VERSION 5.8 ;
BUSBITCHARS "[]" ;
DIVIDERCHAR "/" ;
UNITS
    DATABASE MICRONS 1000 ;
END UNITS

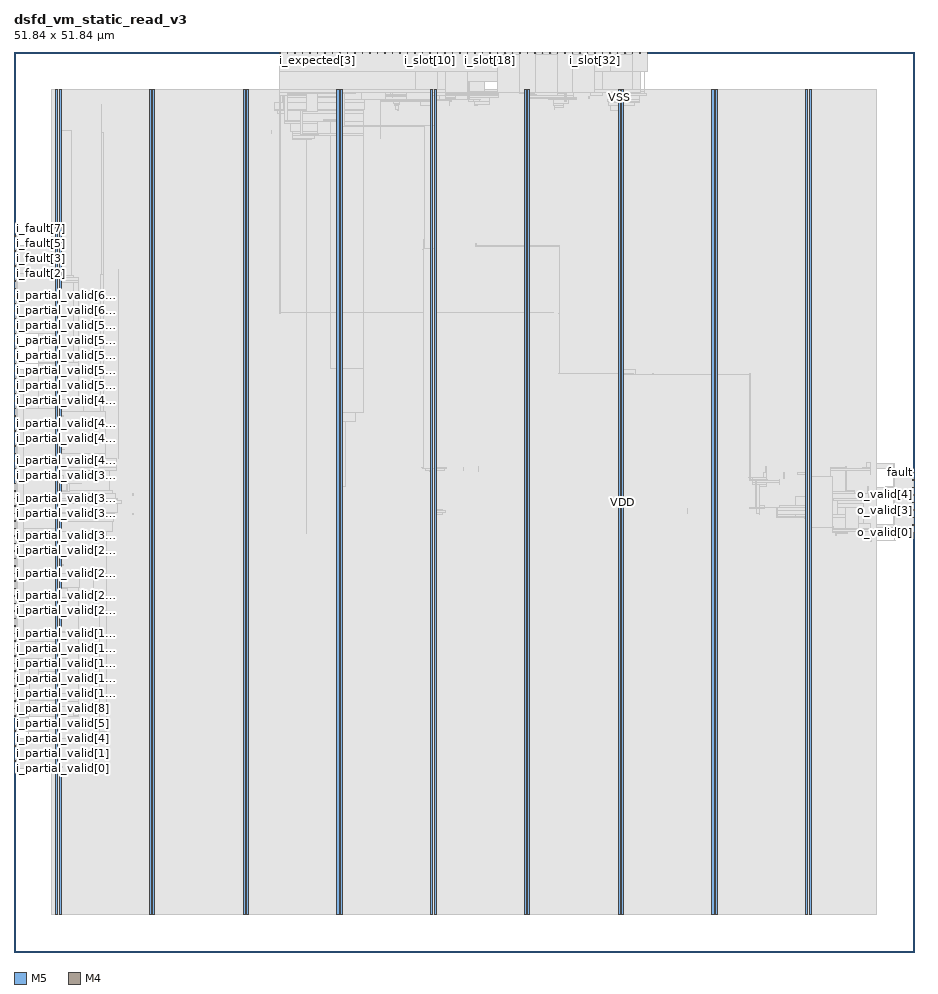
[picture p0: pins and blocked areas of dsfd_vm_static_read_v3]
MACRO dsfd_vm_static_read_v3
  FOREIGN dsfd_vm_static_read_v3 0 0 ;
  CLASS BLOCK ;
  SIZE 51.84 BY 51.84 ;
  PIN ck
    DIRECTION INPUT ;
    USE SIGNAL ;
    PORT
      LAYER M5 ;
        RECT  15.312 51.756 15.336 51.84 ;
    END
  END ck
  PIN fault
    DIRECTION OUTPUT ;
    USE SIGNAL ;
    PORT
      LAYER M4 ;
        RECT  51.756 27.6 51.84 27.624 ;
    END
  END fault
  PIN i_expected[0]
    DIRECTION INPUT ;
    USE SIGNAL ;
    PORT
      LAYER M5 ;
        RECT  16.176 51.756 16.2 51.84 ;
    END
  END i_expected[0]
  PIN i_expected[1]
    DIRECTION INPUT ;
    USE SIGNAL ;
    PORT
      LAYER M5 ;
        RECT  16.608 51.756 16.632 51.84 ;
    END
  END i_expected[1]
  PIN i_expected[2]
    DIRECTION INPUT ;
    USE SIGNAL ;
    PORT
      LAYER M5 ;
        RECT  17.04 51.756 17.064 51.84 ;
    END
  END i_expected[2]
  PIN i_expected[3]
    DIRECTION INPUT ;
    USE SIGNAL ;
    PORT
      LAYER M5 ;
        RECT  17.472 51.756 17.496 51.84 ;
    END
  END i_expected[3]
  PIN i_expected[4]
    DIRECTION INPUT ;
    USE SIGNAL ;
    PORT
      LAYER M5 ;
        RECT  17.904 51.756 17.928 51.84 ;
    END
  END i_expected[4]
  PIN i_expected[5]
    DIRECTION INPUT ;
    USE SIGNAL ;
    PORT
      LAYER M5 ;
        RECT  18.336 51.756 18.36 51.84 ;
    END
  END i_expected[5]
  PIN i_expected[6]
    DIRECTION INPUT ;
    USE SIGNAL ;
    PORT
      LAYER M5 ;
        RECT  18.768 51.756 18.792 51.84 ;
    END
  END i_expected[6]
  PIN i_expected[7]
    DIRECTION INPUT ;
    USE SIGNAL ;
    PORT
      LAYER M5 ;
        RECT  19.2 51.756 19.224 51.84 ;
    END
  END i_expected[7]
  PIN i_fault[0]
    DIRECTION INPUT ;
    USE SIGNAL ;
    PORT
      LAYER M4 ;
        RECT  0 38.208 0.084 38.232 ;
    END
  END i_fault[0]
  PIN i_fault[1]
    DIRECTION INPUT ;
    USE SIGNAL ;
    PORT
      LAYER M4 ;
        RECT  0 38.64 0.084 38.664 ;
    END
  END i_fault[1]
  PIN i_fault[2]
    DIRECTION INPUT ;
    USE SIGNAL ;
    PORT
      LAYER M4 ;
        RECT  0 39.072 0.084 39.096 ;
    END
  END i_fault[2]
  PIN i_fault[3]
    DIRECTION INPUT ;
    USE SIGNAL ;
    PORT
      LAYER M4 ;
        RECT  0 39.504 0.084 39.528 ;
    END
  END i_fault[3]
  PIN i_fault[4]
    DIRECTION INPUT ;
    USE SIGNAL ;
    PORT
      LAYER M4 ;
        RECT  0 39.936 0.084 39.96 ;
    END
  END i_fault[4]
  PIN i_fault[5]
    DIRECTION INPUT ;
    USE SIGNAL ;
    PORT
      LAYER M4 ;
        RECT  0 40.368 0.084 40.392 ;
    END
  END i_fault[5]
  PIN i_fault[6]
    DIRECTION INPUT ;
    USE SIGNAL ;
    PORT
      LAYER M4 ;
        RECT  0 40.8 0.084 40.824 ;
    END
  END i_fault[6]
  PIN i_fault[7]
    DIRECTION INPUT ;
    USE SIGNAL ;
    PORT
      LAYER M4 ;
        RECT  0 41.232 0.084 41.256 ;
    END
  END i_fault[7]
  PIN i_partial_valid[0]
    DIRECTION INPUT ;
    USE SIGNAL ;
    PORT
      LAYER M4 ;
        RECT  0 10.56 0.084 10.584 ;
    END
  END i_partial_valid[0]
  PIN i_partial_valid[10]
    DIRECTION INPUT ;
    USE SIGNAL ;
    PORT
      LAYER M4 ;
        RECT  0 14.88 0.084 14.904 ;
    END
  END i_partial_valid[10]
  PIN i_partial_valid[11]
    DIRECTION INPUT ;
    USE SIGNAL ;
    PORT
      LAYER M4 ;
        RECT  0 15.312 0.084 15.336 ;
    END
  END i_partial_valid[11]
  PIN i_partial_valid[12]
    DIRECTION INPUT ;
    USE SIGNAL ;
    PORT
      LAYER M4 ;
        RECT  0 15.744 0.084 15.768 ;
    END
  END i_partial_valid[12]
  PIN i_partial_valid[13]
    DIRECTION INPUT ;
    USE SIGNAL ;
    PORT
      LAYER M4 ;
        RECT  0 16.176 0.084 16.2 ;
    END
  END i_partial_valid[13]
  PIN i_partial_valid[14]
    DIRECTION INPUT ;
    USE SIGNAL ;
    PORT
      LAYER M4 ;
        RECT  0 16.608 0.084 16.632 ;
    END
  END i_partial_valid[14]
  PIN i_partial_valid[15]
    DIRECTION INPUT ;
    USE SIGNAL ;
    PORT
      LAYER M4 ;
        RECT  0 17.04 0.084 17.064 ;
    END
  END i_partial_valid[15]
  PIN i_partial_valid[16]
    DIRECTION INPUT ;
    USE SIGNAL ;
    PORT
      LAYER M4 ;
        RECT  0 17.472 0.084 17.496 ;
    END
  END i_partial_valid[16]
  PIN i_partial_valid[17]
    DIRECTION INPUT ;
    USE SIGNAL ;
    PORT
      LAYER M4 ;
        RECT  0 17.904 0.084 17.928 ;
    END
  END i_partial_valid[17]
  PIN i_partial_valid[18]
    DIRECTION INPUT ;
    USE SIGNAL ;
    PORT
      LAYER M4 ;
        RECT  0 18.336 0.084 18.36 ;
    END
  END i_partial_valid[18]
  PIN i_partial_valid[19]
    DIRECTION INPUT ;
    USE SIGNAL ;
    PORT
      LAYER M4 ;
        RECT  0 18.768 0.084 18.792 ;
    END
  END i_partial_valid[19]
  PIN i_partial_valid[1]
    DIRECTION INPUT ;
    USE SIGNAL ;
    PORT
      LAYER M4 ;
        RECT  0 10.992 0.084 11.016 ;
    END
  END i_partial_valid[1]
  PIN i_partial_valid[20]
    DIRECTION INPUT ;
    USE SIGNAL ;
    PORT
      LAYER M4 ;
        RECT  0 19.2 0.084 19.224 ;
    END
  END i_partial_valid[20]
  PIN i_partial_valid[21]
    DIRECTION INPUT ;
    USE SIGNAL ;
    PORT
      LAYER M4 ;
        RECT  0 19.632 0.084 19.656 ;
    END
  END i_partial_valid[21]
  PIN i_partial_valid[22]
    DIRECTION INPUT ;
    USE SIGNAL ;
    PORT
      LAYER M4 ;
        RECT  0 20.064 0.084 20.088 ;
    END
  END i_partial_valid[22]
  PIN i_partial_valid[23]
    DIRECTION INPUT ;
    USE SIGNAL ;
    PORT
      LAYER M4 ;
        RECT  0 20.496 0.084 20.52 ;
    END
  END i_partial_valid[23]
  PIN i_partial_valid[24]
    DIRECTION INPUT ;
    USE SIGNAL ;
    PORT
      LAYER M4 ;
        RECT  0 20.928 0.084 20.952 ;
    END
  END i_partial_valid[24]
  PIN i_partial_valid[25]
    DIRECTION INPUT ;
    USE SIGNAL ;
    PORT
      LAYER M4 ;
        RECT  0 21.36 0.084 21.384 ;
    END
  END i_partial_valid[25]
  PIN i_partial_valid[26]
    DIRECTION INPUT ;
    USE SIGNAL ;
    PORT
      LAYER M4 ;
        RECT  0 21.792 0.084 21.816 ;
    END
  END i_partial_valid[26]
  PIN i_partial_valid[27]
    DIRECTION INPUT ;
    USE SIGNAL ;
    PORT
      LAYER M4 ;
        RECT  0 22.224 0.084 22.248 ;
    END
  END i_partial_valid[27]
  PIN i_partial_valid[28]
    DIRECTION INPUT ;
    USE SIGNAL ;
    PORT
      LAYER M4 ;
        RECT  0 22.656 0.084 22.68 ;
    END
  END i_partial_valid[28]
  PIN i_partial_valid[29]
    DIRECTION INPUT ;
    USE SIGNAL ;
    PORT
      LAYER M4 ;
        RECT  0 23.088 0.084 23.112 ;
    END
  END i_partial_valid[29]
  PIN i_partial_valid[2]
    DIRECTION INPUT ;
    USE SIGNAL ;
    PORT
      LAYER M4 ;
        RECT  0 11.424 0.084 11.448 ;
    END
  END i_partial_valid[2]
  PIN i_partial_valid[30]
    DIRECTION INPUT ;
    USE SIGNAL ;
    PORT
      LAYER M4 ;
        RECT  0 23.52 0.084 23.544 ;
    END
  END i_partial_valid[30]
  PIN i_partial_valid[31]
    DIRECTION INPUT ;
    USE SIGNAL ;
    PORT
      LAYER M4 ;
        RECT  0 23.952 0.084 23.976 ;
    END
  END i_partial_valid[31]
  PIN i_partial_valid[32]
    DIRECTION INPUT ;
    USE SIGNAL ;
    PORT
      LAYER M4 ;
        RECT  0 24.384 0.084 24.408 ;
    END
  END i_partial_valid[32]
  PIN i_partial_valid[33]
    DIRECTION INPUT ;
    USE SIGNAL ;
    PORT
      LAYER M4 ;
        RECT  0 24.816 0.084 24.84 ;
    END
  END i_partial_valid[33]
  PIN i_partial_valid[34]
    DIRECTION INPUT ;
    USE SIGNAL ;
    PORT
      LAYER M4 ;
        RECT  0 25.248 0.084 25.272 ;
    END
  END i_partial_valid[34]
  PIN i_partial_valid[35]
    DIRECTION INPUT ;
    USE SIGNAL ;
    PORT
      LAYER M4 ;
        RECT  0 25.68 0.084 25.704 ;
    END
  END i_partial_valid[35]
  PIN i_partial_valid[36]
    DIRECTION INPUT ;
    USE SIGNAL ;
    PORT
      LAYER M4 ;
        RECT  0 26.112 0.084 26.136 ;
    END
  END i_partial_valid[36]
  PIN i_partial_valid[37]
    DIRECTION INPUT ;
    USE SIGNAL ;
    PORT
      LAYER M4 ;
        RECT  0 26.544 0.084 26.568 ;
    END
  END i_partial_valid[37]
  PIN i_partial_valid[38]
    DIRECTION INPUT ;
    USE SIGNAL ;
    PORT
      LAYER M4 ;
        RECT  0 26.976 0.084 27 ;
    END
  END i_partial_valid[38]
  PIN i_partial_valid[39]
    DIRECTION INPUT ;
    USE SIGNAL ;
    PORT
      LAYER M4 ;
        RECT  0 27.408 0.084 27.432 ;
    END
  END i_partial_valid[39]
  PIN i_partial_valid[3]
    DIRECTION INPUT ;
    USE SIGNAL ;
    PORT
      LAYER M4 ;
        RECT  0 11.856 0.084 11.88 ;
    END
  END i_partial_valid[3]
  PIN i_partial_valid[40]
    DIRECTION INPUT ;
    USE SIGNAL ;
    PORT
      LAYER M4 ;
        RECT  0 27.84 0.084 27.864 ;
    END
  END i_partial_valid[40]
  PIN i_partial_valid[41]
    DIRECTION INPUT ;
    USE SIGNAL ;
    PORT
      LAYER M4 ;
        RECT  0 28.272 0.084 28.296 ;
    END
  END i_partial_valid[41]
  PIN i_partial_valid[42]
    DIRECTION INPUT ;
    USE SIGNAL ;
    PORT
      LAYER M4 ;
        RECT  0 28.704 0.084 28.728 ;
    END
  END i_partial_valid[42]
  PIN i_partial_valid[43]
    DIRECTION INPUT ;
    USE SIGNAL ;
    PORT
      LAYER M4 ;
        RECT  0 29.136 0.084 29.16 ;
    END
  END i_partial_valid[43]
  PIN i_partial_valid[44]
    DIRECTION INPUT ;
    USE SIGNAL ;
    PORT
      LAYER M4 ;
        RECT  0 29.568 0.084 29.592 ;
    END
  END i_partial_valid[44]
  PIN i_partial_valid[45]
    DIRECTION INPUT ;
    USE SIGNAL ;
    PORT
      LAYER M4 ;
        RECT  0 30 0.084 30.024 ;
    END
  END i_partial_valid[45]
  PIN i_partial_valid[46]
    DIRECTION INPUT ;
    USE SIGNAL ;
    PORT
      LAYER M4 ;
        RECT  0 30.432 0.084 30.456 ;
    END
  END i_partial_valid[46]
  PIN i_partial_valid[47]
    DIRECTION INPUT ;
    USE SIGNAL ;
    PORT
      LAYER M4 ;
        RECT  0 30.864 0.084 30.888 ;
    END
  END i_partial_valid[47]
  PIN i_partial_valid[48]
    DIRECTION INPUT ;
    USE SIGNAL ;
    PORT
      LAYER M4 ;
        RECT  0 31.296 0.084 31.32 ;
    END
  END i_partial_valid[48]
  PIN i_partial_valid[49]
    DIRECTION INPUT ;
    USE SIGNAL ;
    PORT
      LAYER M4 ;
        RECT  0 31.728 0.084 31.752 ;
    END
  END i_partial_valid[49]
  PIN i_partial_valid[4]
    DIRECTION INPUT ;
    USE SIGNAL ;
    PORT
      LAYER M4 ;
        RECT  0 12.288 0.084 12.312 ;
    END
  END i_partial_valid[4]
  PIN i_partial_valid[50]
    DIRECTION INPUT ;
    USE SIGNAL ;
    PORT
      LAYER M4 ;
        RECT  0 32.16 0.084 32.184 ;
    END
  END i_partial_valid[50]
  PIN i_partial_valid[51]
    DIRECTION INPUT ;
    USE SIGNAL ;
    PORT
      LAYER M4 ;
        RECT  0 32.592 0.084 32.616 ;
    END
  END i_partial_valid[51]
  PIN i_partial_valid[52]
    DIRECTION INPUT ;
    USE SIGNAL ;
    PORT
      LAYER M4 ;
        RECT  0 33.024 0.084 33.048 ;
    END
  END i_partial_valid[52]
  PIN i_partial_valid[53]
    DIRECTION INPUT ;
    USE SIGNAL ;
    PORT
      LAYER M4 ;
        RECT  0 33.456 0.084 33.48 ;
    END
  END i_partial_valid[53]
  PIN i_partial_valid[54]
    DIRECTION INPUT ;
    USE SIGNAL ;
    PORT
      LAYER M4 ;
        RECT  0 33.888 0.084 33.912 ;
    END
  END i_partial_valid[54]
  PIN i_partial_valid[55]
    DIRECTION INPUT ;
    USE SIGNAL ;
    PORT
      LAYER M4 ;
        RECT  0 34.32 0.084 34.344 ;
    END
  END i_partial_valid[55]
  PIN i_partial_valid[56]
    DIRECTION INPUT ;
    USE SIGNAL ;
    PORT
      LAYER M4 ;
        RECT  0 34.752 0.084 34.776 ;
    END
  END i_partial_valid[56]
  PIN i_partial_valid[57]
    DIRECTION INPUT ;
    USE SIGNAL ;
    PORT
      LAYER M4 ;
        RECT  0 35.184 0.084 35.208 ;
    END
  END i_partial_valid[57]
  PIN i_partial_valid[58]
    DIRECTION INPUT ;
    USE SIGNAL ;
    PORT
      LAYER M4 ;
        RECT  0 35.616 0.084 35.64 ;
    END
  END i_partial_valid[58]
  PIN i_partial_valid[59]
    DIRECTION INPUT ;
    USE SIGNAL ;
    PORT
      LAYER M4 ;
        RECT  0 36.048 0.084 36.072 ;
    END
  END i_partial_valid[59]
  PIN i_partial_valid[5]
    DIRECTION INPUT ;
    USE SIGNAL ;
    PORT
      LAYER M4 ;
        RECT  0 12.72 0.084 12.744 ;
    END
  END i_partial_valid[5]
  PIN i_partial_valid[60]
    DIRECTION INPUT ;
    USE SIGNAL ;
    PORT
      LAYER M4 ;
        RECT  0 36.48 0.084 36.504 ;
    END
  END i_partial_valid[60]
  PIN i_partial_valid[61]
    DIRECTION INPUT ;
    USE SIGNAL ;
    PORT
      LAYER M4 ;
        RECT  0 36.912 0.084 36.936 ;
    END
  END i_partial_valid[61]
  PIN i_partial_valid[62]
    DIRECTION INPUT ;
    USE SIGNAL ;
    PORT
      LAYER M4 ;
        RECT  0 37.344 0.084 37.368 ;
    END
  END i_partial_valid[62]
  PIN i_partial_valid[63]
    DIRECTION INPUT ;
    USE SIGNAL ;
    PORT
      LAYER M4 ;
        RECT  0 37.776 0.084 37.8 ;
    END
  END i_partial_valid[63]
  PIN i_partial_valid[6]
    DIRECTION INPUT ;
    USE SIGNAL ;
    PORT
      LAYER M4 ;
        RECT  0 13.152 0.084 13.176 ;
    END
  END i_partial_valid[6]
  PIN i_partial_valid[7]
    DIRECTION INPUT ;
    USE SIGNAL ;
    PORT
      LAYER M4 ;
        RECT  0 13.584 0.084 13.608 ;
    END
  END i_partial_valid[7]
  PIN i_partial_valid[8]
    DIRECTION INPUT ;
    USE SIGNAL ;
    PORT
      LAYER M4 ;
        RECT  0 14.016 0.084 14.04 ;
    END
  END i_partial_valid[8]
  PIN i_partial_valid[9]
    DIRECTION INPUT ;
    USE SIGNAL ;
    PORT
      LAYER M4 ;
        RECT  0 14.448 0.084 14.472 ;
    END
  END i_partial_valid[9]
  PIN i_slot[0]
    DIRECTION INPUT ;
    USE SIGNAL ;
    PORT
      LAYER M5 ;
        RECT  19.632 51.756 19.656 51.84 ;
    END
  END i_slot[0]
  PIN i_slot[10]
    DIRECTION INPUT ;
    USE SIGNAL ;
    PORT
      LAYER M5 ;
        RECT  23.952 51.756 23.976 51.84 ;
    END
  END i_slot[10]
  PIN i_slot[11]
    DIRECTION INPUT ;
    USE SIGNAL ;
    PORT
      LAYER M5 ;
        RECT  24.384 51.756 24.408 51.84 ;
    END
  END i_slot[11]
  PIN i_slot[12]
    DIRECTION INPUT ;
    USE SIGNAL ;
    PORT
      LAYER M5 ;
        RECT  24.816 51.756 24.84 51.84 ;
    END
  END i_slot[12]
  PIN i_slot[13]
    DIRECTION INPUT ;
    USE SIGNAL ;
    PORT
      LAYER M5 ;
        RECT  25.248 51.756 25.272 51.84 ;
    END
  END i_slot[13]
  PIN i_slot[14]
    DIRECTION INPUT ;
    USE SIGNAL ;
    PORT
      LAYER M5 ;
        RECT  25.68 51.756 25.704 51.84 ;
    END
  END i_slot[14]
  PIN i_slot[15]
    DIRECTION INPUT ;
    USE SIGNAL ;
    PORT
      LAYER M5 ;
        RECT  26.112 51.756 26.136 51.84 ;
    END
  END i_slot[15]
  PIN i_slot[16]
    DIRECTION INPUT ;
    USE SIGNAL ;
    PORT
      LAYER M5 ;
        RECT  26.544 51.756 26.568 51.84 ;
    END
  END i_slot[16]
  PIN i_slot[17]
    DIRECTION INPUT ;
    USE SIGNAL ;
    PORT
      LAYER M5 ;
        RECT  26.976 51.756 27 51.84 ;
    END
  END i_slot[17]
  PIN i_slot[18]
    DIRECTION INPUT ;
    USE SIGNAL ;
    PORT
      LAYER M5 ;
        RECT  27.408 51.756 27.432 51.84 ;
    END
  END i_slot[18]
  PIN i_slot[19]
    DIRECTION INPUT ;
    USE SIGNAL ;
    PORT
      LAYER M5 ;
        RECT  27.84 51.756 27.864 51.84 ;
    END
  END i_slot[19]
  PIN i_slot[1]
    DIRECTION INPUT ;
    USE SIGNAL ;
    PORT
      LAYER M5 ;
        RECT  20.064 51.756 20.088 51.84 ;
    END
  END i_slot[1]
  PIN i_slot[20]
    DIRECTION INPUT ;
    USE SIGNAL ;
    PORT
      LAYER M5 ;
        RECT  28.272 51.756 28.296 51.84 ;
    END
  END i_slot[20]
  PIN i_slot[21]
    DIRECTION INPUT ;
    USE SIGNAL ;
    PORT
      LAYER M5 ;
        RECT  28.704 51.756 28.728 51.84 ;
    END
  END i_slot[21]
  PIN i_slot[22]
    DIRECTION INPUT ;
    USE SIGNAL ;
    PORT
      LAYER M5 ;
        RECT  29.136 51.756 29.16 51.84 ;
    END
  END i_slot[22]
  PIN i_slot[23]
    DIRECTION INPUT ;
    USE SIGNAL ;
    PORT
      LAYER M5 ;
        RECT  29.568 51.756 29.592 51.84 ;
    END
  END i_slot[23]
  PIN i_slot[24]
    DIRECTION INPUT ;
    USE SIGNAL ;
    PORT
      LAYER M5 ;
        RECT  30 51.756 30.024 51.84 ;
    END
  END i_slot[24]
  PIN i_slot[25]
    DIRECTION INPUT ;
    USE SIGNAL ;
    PORT
      LAYER M5 ;
        RECT  30.432 51.756 30.456 51.84 ;
    END
  END i_slot[25]
  PIN i_slot[26]
    DIRECTION INPUT ;
    USE SIGNAL ;
    PORT
      LAYER M5 ;
        RECT  30.864 51.756 30.888 51.84 ;
    END
  END i_slot[26]
  PIN i_slot[27]
    DIRECTION INPUT ;
    USE SIGNAL ;
    PORT
      LAYER M5 ;
        RECT  31.296 51.756 31.32 51.84 ;
    END
  END i_slot[27]
  PIN i_slot[28]
    DIRECTION INPUT ;
    USE SIGNAL ;
    PORT
      LAYER M5 ;
        RECT  31.728 51.756 31.752 51.84 ;
    END
  END i_slot[28]
  PIN i_slot[29]
    DIRECTION INPUT ;
    USE SIGNAL ;
    PORT
      LAYER M5 ;
        RECT  32.16 51.756 32.184 51.84 ;
    END
  END i_slot[29]
  PIN i_slot[2]
    DIRECTION INPUT ;
    USE SIGNAL ;
    PORT
      LAYER M5 ;
        RECT  20.496 51.756 20.52 51.84 ;
    END
  END i_slot[2]
  PIN i_slot[30]
    DIRECTION INPUT ;
    USE SIGNAL ;
    PORT
      LAYER M5 ;
        RECT  32.592 51.756 32.616 51.84 ;
    END
  END i_slot[30]
  PIN i_slot[31]
    DIRECTION INPUT ;
    USE SIGNAL ;
    PORT
      LAYER M5 ;
        RECT  33.024 51.756 33.048 51.84 ;
    END
  END i_slot[31]
  PIN i_slot[32]
    DIRECTION INPUT ;
    USE SIGNAL ;
    PORT
      LAYER M5 ;
        RECT  33.456 51.756 33.48 51.84 ;
    END
  END i_slot[32]
  PIN i_slot[33]
    DIRECTION INPUT ;
    USE SIGNAL ;
    PORT
      LAYER M5 ;
        RECT  33.888 51.756 33.912 51.84 ;
    END
  END i_slot[33]
  PIN i_slot[34]
    DIRECTION INPUT ;
    USE SIGNAL ;
    PORT
      LAYER M5 ;
        RECT  34.32 51.756 34.344 51.84 ;
    END
  END i_slot[34]
  PIN i_slot[35]
    DIRECTION INPUT ;
    USE SIGNAL ;
    PORT
      LAYER M5 ;
        RECT  34.752 51.756 34.776 51.84 ;
    END
  END i_slot[35]
  PIN i_slot[36]
    DIRECTION INPUT ;
    USE SIGNAL ;
    PORT
      LAYER M5 ;
        RECT  35.184 51.756 35.208 51.84 ;
    END
  END i_slot[36]
  PIN i_slot[37]
    DIRECTION INPUT ;
    USE SIGNAL ;
    PORT
      LAYER M5 ;
        RECT  35.616 51.756 35.64 51.84 ;
    END
  END i_slot[37]
  PIN i_slot[38]
    DIRECTION INPUT ;
    USE SIGNAL ;
    PORT
      LAYER M5 ;
        RECT  36.048 51.756 36.072 51.84 ;
    END
  END i_slot[38]
  PIN i_slot[39]
    DIRECTION INPUT ;
    USE SIGNAL ;
    PORT
      LAYER M5 ;
        RECT  36.48 51.756 36.504 51.84 ;
    END
  END i_slot[39]
  PIN i_slot[3]
    DIRECTION INPUT ;
    USE SIGNAL ;
    PORT
      LAYER M5 ;
        RECT  20.928 51.756 20.952 51.84 ;
    END
  END i_slot[3]
  PIN i_slot[4]
    DIRECTION INPUT ;
    USE SIGNAL ;
    PORT
      LAYER M5 ;
        RECT  21.36 51.756 21.384 51.84 ;
    END
  END i_slot[4]
  PIN i_slot[5]
    DIRECTION INPUT ;
    USE SIGNAL ;
    PORT
      LAYER M5 ;
        RECT  21.792 51.756 21.816 51.84 ;
    END
  END i_slot[5]
  PIN i_slot[6]
    DIRECTION INPUT ;
    USE SIGNAL ;
    PORT
      LAYER M5 ;
        RECT  22.224 51.756 22.248 51.84 ;
    END
  END i_slot[6]
  PIN i_slot[7]
    DIRECTION INPUT ;
    USE SIGNAL ;
    PORT
      LAYER M5 ;
        RECT  22.656 51.756 22.68 51.84 ;
    END
  END i_slot[7]
  PIN i_slot[8]
    DIRECTION INPUT ;
    USE SIGNAL ;
    PORT
      LAYER M5 ;
        RECT  23.088 51.756 23.112 51.84 ;
    END
  END i_slot[8]
  PIN i_slot[9]
    DIRECTION INPUT ;
    USE SIGNAL ;
    PORT
      LAYER M5 ;
        RECT  23.52 51.756 23.544 51.84 ;
    END
  END i_slot[9]
  PIN o_valid[0]
    DIRECTION OUTPUT ;
    USE SIGNAL ;
    PORT
      LAYER M4 ;
        RECT  51.756 24.144 51.84 24.168 ;
    END
  END o_valid[0]
  PIN o_valid[1]
    DIRECTION OUTPUT ;
    USE SIGNAL ;
    PORT
      LAYER M4 ;
        RECT  51.756 24.576 51.84 24.6 ;
    END
  END o_valid[1]
  PIN o_valid[2]
    DIRECTION OUTPUT ;
    USE SIGNAL ;
    PORT
      LAYER M4 ;
        RECT  51.756 25.008 51.84 25.032 ;
    END
  END o_valid[2]
  PIN o_valid[3]
    DIRECTION OUTPUT ;
    USE SIGNAL ;
    PORT
      LAYER M4 ;
        RECT  51.756 25.44 51.84 25.464 ;
    END
  END o_valid[3]
  PIN o_valid[4]
    DIRECTION OUTPUT ;
    USE SIGNAL ;
    PORT
      LAYER M4 ;
        RECT  51.756 25.872 51.84 25.896 ;
    END
  END o_valid[4]
  PIN o_valid[5]
    DIRECTION OUTPUT ;
    USE SIGNAL ;
    PORT
      LAYER M4 ;
        RECT  51.756 26.304 51.84 26.328 ;
    END
  END o_valid[5]
  PIN o_valid[6]
    DIRECTION OUTPUT ;
    USE SIGNAL ;
    PORT
      LAYER M4 ;
        RECT  51.756 26.736 51.84 26.76 ;
    END
  END o_valid[6]
  PIN o_valid[7]
    DIRECTION OUTPUT ;
    USE SIGNAL ;
    PORT
      LAYER M4 ;
        RECT  51.756 27.168 51.84 27.192 ;
    END
  END o_valid[7]
  PIN rst_n
    DIRECTION INPUT ;
    USE SIGNAL ;
    PORT
      LAYER M5 ;
        RECT  15.744 51.756 15.768 51.84 ;
    END
  END rst_n
  PIN VDD
    DIRECTION INOUT ;
    USE POWER ;
    PORT
      LAYER M5 ;
        RECT  45.792 2.151 45.912 49.689 ;
        RECT  40.392 2.151 40.512 49.689 ;
        RECT  34.992 2.151 35.112 49.689 ;
        RECT  29.592 2.151 29.712 49.689 ;
        RECT  24.192 2.151 24.312 49.689 ;
        RECT  18.792 2.151 18.912 49.689 ;
        RECT  13.392 2.151 13.512 49.689 ;
        RECT  7.992 2.151 8.112 49.689 ;
        RECT  2.592 2.151 2.712 49.689 ;
    END
  END VDD
  PIN VSS
    DIRECTION INOUT ;
    USE GROUND ;
    PORT
      LAYER M5 ;
        RECT  45.6 2.137 45.72 49.703 ;
        RECT  40.2 2.137 40.32 49.703 ;
        RECT  34.8 2.137 34.92 49.703 ;
        RECT  29.4 2.137 29.52 49.703 ;
        RECT  24 2.137 24.12 49.703 ;
        RECT  18.6 2.137 18.72 49.703 ;
        RECT  13.2 2.137 13.32 49.703 ;
        RECT  7.8 2.137 7.92 49.703 ;
        RECT  2.4 2.137 2.52 49.703 ;
    END
  END VSS
  # OT_OBS_CLOSED layer=M5 d_um=1.536 added=22
  OBS
    LAYER RVTN ;
     RECT  2.16 2.16 49.68 2.295 ;
     RECT  2.16 2.565 49.68 2.835 ;
     RECT  2.16 3.105 49.68 3.375 ;
     RECT  2.16 3.645 49.68 3.915 ;
     RECT  2.16 4.185 49.68 4.455 ;
     RECT  2.16 4.725 49.68 4.995 ;
     RECT  2.16 5.265 49.68 5.535 ;
     RECT  2.16 5.805 49.68 6.075 ;
     RECT  2.16 6.345 49.68 6.615 ;
     RECT  2.16 6.885 49.68 7.155 ;
     RECT  2.16 7.425 49.68 7.695 ;
     RECT  2.16 7.965 49.68 8.235 ;
     RECT  2.16 8.505 49.68 8.775 ;
     RECT  2.16 9.045 49.68 9.315 ;
     RECT  2.16 9.585 49.68 9.855 ;
     RECT  2.16 10.125 49.68 10.395 ;
     RECT  2.16 10.665 49.68 10.935 ;
     RECT  2.16 11.205 49.68 11.475 ;
     RECT  2.16 11.745 49.68 12.015 ;
     RECT  2.16 12.285 49.68 12.555 ;
     RECT  2.16 12.825 49.68 13.095 ;
     RECT  2.16 13.365 49.68 13.635 ;
     RECT  2.16 13.905 49.68 14.175 ;
     RECT  2.16 14.445 49.68 14.715 ;
     RECT  2.16 14.985 49.68 15.255 ;
     RECT  2.16 15.525 49.68 15.795 ;
     RECT  2.16 16.065 49.68 16.335 ;
     RECT  2.16 16.605 49.68 16.875 ;
     RECT  2.16 17.145 49.68 17.415 ;
     RECT  2.16 17.685 49.68 17.955 ;
     RECT  2.16 18.225 49.68 18.495 ;
     RECT  2.16 18.765 49.68 19.035 ;
     RECT  2.16 19.305 49.68 19.575 ;
     RECT  2.16 19.845 49.68 20.115 ;
     RECT  2.16 20.385 49.68 20.655 ;
     RECT  2.16 20.925 49.68 21.195 ;
     RECT  2.16 21.465 49.68 21.735 ;
     RECT  2.16 22.005 49.68 22.275 ;
     RECT  2.16 22.545 49.68 22.815 ;
     RECT  2.16 23.085 49.68 23.355 ;
     RECT  2.16 23.625 49.68 23.895 ;
     RECT  2.16 24.165 49.68 24.435 ;
     RECT  2.16 24.705 49.68 24.975 ;
     RECT  2.16 25.245 49.68 25.515 ;
     RECT  2.16 25.785 49.68 26.055 ;
     RECT  2.16 26.325 49.68 26.595 ;
     RECT  2.16 26.865 49.68 27.135 ;
     RECT  2.16 27.405 49.68 27.675 ;
     RECT  2.16 27.945 49.68 28.215 ;
     RECT  2.16 28.485 49.68 28.755 ;
     RECT  2.16 29.025 49.68 29.295 ;
     RECT  2.16 29.565 49.68 29.835 ;
     RECT  2.16 30.105 49.68 30.375 ;
     RECT  2.16 30.645 49.68 30.915 ;
     RECT  2.16 31.185 49.68 31.455 ;
     RECT  2.16 31.725 49.68 31.995 ;
     RECT  2.16 32.265 49.68 32.535 ;
     RECT  2.16 32.805 49.68 33.075 ;
     RECT  2.16 33.345 49.68 33.615 ;
     RECT  2.16 33.885 49.68 34.155 ;
     RECT  2.16 34.425 49.68 34.695 ;
     RECT  2.16 34.965 49.68 35.235 ;
     RECT  2.16 35.505 49.68 35.775 ;
     RECT  2.16 36.045 49.68 36.315 ;
     RECT  2.16 36.585 49.68 36.855 ;
     RECT  2.16 37.125 49.68 37.395 ;
     RECT  2.16 37.665 49.68 37.935 ;
     RECT  2.16 38.205 49.68 38.475 ;
     RECT  2.16 38.745 49.68 39.015 ;
     RECT  2.16 39.285 49.68 39.555 ;
     RECT  2.16 39.825 49.68 40.095 ;
     RECT  2.16 40.365 49.68 40.635 ;
     RECT  2.16 40.905 49.68 41.175 ;
     RECT  2.16 41.445 49.68 41.715 ;
     RECT  2.16 41.985 49.68 42.255 ;
     RECT  2.16 42.525 49.68 42.795 ;
     RECT  2.16 43.065 49.68 43.335 ;
     RECT  2.16 43.605 49.68 43.875 ;
     RECT  2.16 44.145 49.68 44.415 ;
     RECT  2.16 44.685 49.68 44.955 ;
     RECT  2.16 45.225 49.68 45.495 ;
     RECT  2.16 45.765 49.68 46.035 ;
     RECT  2.16 46.305 49.68 46.575 ;
     RECT  2.16 46.845 49.68 47.115 ;
     RECT  2.16 47.385 49.68 47.655 ;
     RECT  2.16 47.925 49.68 48.195 ;
     RECT  2.16 48.465 49.68 48.735 ;
     RECT  2.16 49.005 49.68 49.275 ;
     RECT  2.16 49.545 49.68 49.68 ;
    LAYER RVTP ;
     RECT  2.16 2.295 49.68 2.565 ;
     RECT  2.16 2.835 49.68 3.105 ;
     RECT  2.16 3.375 49.68 3.645 ;
     RECT  2.16 3.915 49.68 4.185 ;
     RECT  2.16 4.455 49.68 4.725 ;
     RECT  2.16 4.995 49.68 5.265 ;
     RECT  2.16 5.535 49.68 5.805 ;
     RECT  2.16 6.075 49.68 6.345 ;
     RECT  2.16 6.615 49.68 6.885 ;
     RECT  2.16 7.155 49.68 7.425 ;
     RECT  2.16 7.695 49.68 7.965 ;
     RECT  2.16 8.235 49.68 8.505 ;
     RECT  2.16 8.775 49.68 9.045 ;
     RECT  2.16 9.315 49.68 9.585 ;
     RECT  2.16 9.855 49.68 10.125 ;
     RECT  2.16 10.395 49.68 10.665 ;
     RECT  2.16 10.935 49.68 11.205 ;
     RECT  2.16 11.475 49.68 11.745 ;
     RECT  2.16 12.015 49.68 12.285 ;
     RECT  2.16 12.555 49.68 12.825 ;
     RECT  2.16 13.095 49.68 13.365 ;
     RECT  2.16 13.635 49.68 13.905 ;
     RECT  2.16 14.175 49.68 14.445 ;
     RECT  2.16 14.715 49.68 14.985 ;
     RECT  2.16 15.255 49.68 15.525 ;
     RECT  2.16 15.795 49.68 16.065 ;
     RECT  2.16 16.335 49.68 16.605 ;
     RECT  2.16 16.875 49.68 17.145 ;
     RECT  2.16 17.415 49.68 17.685 ;
     RECT  2.16 17.955 49.68 18.225 ;
     RECT  2.16 18.495 49.68 18.765 ;
     RECT  2.16 19.035 49.68 19.305 ;
     RECT  2.16 19.575 49.68 19.845 ;
     RECT  2.16 20.115 49.68 20.385 ;
     RECT  2.16 20.655 49.68 20.925 ;
     RECT  2.16 21.195 49.68 21.465 ;
     RECT  2.16 21.735 49.68 22.005 ;
     RECT  2.16 22.275 49.68 22.545 ;
     RECT  2.16 22.815 49.68 23.085 ;
     RECT  2.16 23.355 49.68 23.625 ;
     RECT  2.16 23.895 49.68 24.165 ;
     RECT  2.16 24.435 49.68 24.705 ;
     RECT  2.16 24.975 49.68 25.245 ;
     RECT  2.16 25.515 49.68 25.785 ;
     RECT  2.16 26.055 49.68 26.325 ;
     RECT  2.16 26.595 49.68 26.865 ;
     RECT  2.16 27.135 49.68 27.405 ;
     RECT  2.16 27.675 49.68 27.945 ;
     RECT  2.16 28.215 49.68 28.485 ;
     RECT  2.16 28.755 49.68 29.025 ;
     RECT  2.16 29.295 49.68 29.565 ;
     RECT  2.16 29.835 49.68 30.105 ;
     RECT  2.16 30.375 49.68 30.645 ;
     RECT  2.16 30.915 49.68 31.185 ;
     RECT  2.16 31.455 49.68 31.725 ;
     RECT  2.16 31.995 49.68 32.265 ;
     RECT  2.16 32.535 49.68 32.805 ;
     RECT  2.16 33.075 49.68 33.345 ;
     RECT  2.16 33.615 49.68 33.885 ;
     RECT  2.16 34.155 49.68 34.425 ;
     RECT  2.16 34.695 49.68 34.965 ;
     RECT  2.16 35.235 49.68 35.505 ;
     RECT  2.16 35.775 49.68 36.045 ;
     RECT  2.16 36.315 49.68 36.585 ;
     RECT  2.16 36.855 49.68 37.125 ;
     RECT  2.16 37.395 49.68 37.665 ;
     RECT  2.16 37.935 49.68 38.205 ;
     RECT  2.16 38.475 49.68 38.745 ;
     RECT  2.16 39.015 49.68 39.285 ;
     RECT  2.16 39.555 49.68 39.825 ;
     RECT  2.16 40.095 49.68 40.365 ;
     RECT  2.16 40.635 49.68 40.905 ;
     RECT  2.16 41.175 49.68 41.445 ;
     RECT  2.16 41.715 49.68 41.985 ;
     RECT  2.16 42.255 49.68 42.525 ;
     RECT  2.16 42.795 49.68 43.065 ;
     RECT  2.16 43.335 49.68 43.605 ;
     RECT  2.16 43.875 49.68 44.145 ;
     RECT  2.16 44.415 49.68 44.685 ;
     RECT  2.16 44.955 49.68 45.225 ;
     RECT  2.16 45.495 49.68 45.765 ;
     RECT  2.16 46.035 49.68 46.305 ;
     RECT  2.16 46.575 49.68 46.845 ;
     RECT  2.16 47.115 49.68 47.385 ;
     RECT  2.16 47.655 49.68 47.925 ;
     RECT  2.16 48.195 49.68 48.465 ;
     RECT  2.16 48.735 49.68 49.005 ;
     RECT  2.16 49.275 49.68 49.545 ;
    LAYER M1 ;
     RECT  2.16 2.151 49.68 49.689 ;
    LAYER M2 ;
     RECT  0.067 24.336 0.103 24.354 ;
     RECT  0.103 24.336 0.139 24.768 ;
     RECT  0.067 25.56 0.139 25.578 ;
     RECT  0.103 32.04 0.139 32.058 ;
     RECT  0.103 32.85 0.139 33.57 ;
     RECT  0.103 39.06 0.139 40.158 ;
     RECT  0.103 31.122 0.175 31.14 ;
     RECT  0.175 22.05 0.247 22.23 ;
     RECT  0.175 30.726 0.311 31.14 ;
     RECT  0.175 23.13 0.535 23.148 ;
     RECT  0.139 24.336 0.535 25.578 ;
     RECT  0.103 28.962 0.535 29.358 ;
     RECT  0.311 31.122 0.535 31.14 ;
     RECT  0.139 32.04 0.535 33.57 ;
     RECT  0.535 28.458 0.823 29.358 ;
     RECT  0.535 23.13 1.399 25.578 ;
     RECT  0.823 28.422 1.399 29.358 ;
     RECT  0.247 22.014 1.471 22.23 ;
     RECT  1.399 23.13 1.471 26.01 ;
     RECT  1.471 20.862 1.507 20.88 ;
     RECT  1.399 28.26 1.975 29.358 ;
     RECT  1.471 22.014 2.011 26.01 ;
     RECT  0.103 12.726 2.16 12.744 ;
     RECT  1.507 20.322 2.16 20.88 ;
     RECT  2.011 22.014 2.16 26.118 ;
     RECT  0.031 26.946 2.16 26.964 ;
     RECT  1.975 27.918 2.16 29.358 ;
     RECT  0.535 31.122 2.16 33.57 ;
     RECT  0.139 39.06 2.16 40.698 ;
     RECT  2.16 2.151 49.68 49.689 ;
     RECT  49.68 26.226 50.207 26.784 ;
     RECT  49.68 27.846 50.675 28.134 ;
     RECT  49.68 24.48 50.711 24.624 ;
     RECT  49.68 25.452 50.711 25.47 ;
     RECT  50.207 26.226 50.711 26.514 ;
     RECT  50.675 28.116 50.711 28.134 ;
     RECT  49.68 23.706 50.747 23.724 ;
     RECT  50.711 24.48 50.747 24.498 ;
    LAYER M3 ;
     RECT  2.415 2.143 2.505 2.413 ;
     RECT  7.815 2.143 7.905 2.413 ;
     RECT  13.215 2.143 13.305 2.413 ;
     RECT  18.615 2.143 18.705 2.413 ;
     RECT  24.015 2.143 24.105 2.413 ;
     RECT  29.415 2.143 29.505 2.413 ;
     RECT  34.815 2.143 34.905 2.413 ;
     RECT  40.215 2.143 40.305 2.413 ;
     RECT  45.615 2.143 45.705 2.413 ;
     RECT  2.415 2.413 2.697 10.555 ;
     RECT  2.304 10.555 2.697 10.651 ;
     RECT  2.304 10.651 2.754 10.685 ;
     RECT  0.144 10.987 0.162 11.083 ;
     RECT  0.072 11.083 0.162 11.117 ;
     RECT  2.415 10.685 2.754 11.419 ;
     RECT  0.072 11.117 0.09 12.712 ;
     RECT  0.828 11.851 0.846 12.712 ;
     RECT  5.328 12.283 5.346 12.721 ;
     RECT  0.072 12.712 0.846 13.483 ;
     RECT  1.98 11.419 2.754 14.107 ;
     RECT  3.708 13.579 3.726 14.107 ;
     RECT  0.036 13.483 0.846 14.141 ;
     RECT  0.828 14.141 0.846 14.443 ;
     RECT  1.98 14.107 3.726 14.443 ;
     RECT  0.036 14.141 0.09 14.875 ;
     RECT  0.828 14.443 3.726 14.875 ;
     RECT  4.896 12.721 5.346 19.651 ;
     RECT  0.036 14.875 3.726 21.001 ;
     RECT  0.036 21.001 3.798 21.811 ;
     RECT  4.572 19.651 5.346 21.811 ;
     RECT  49.356 23.665 49.374 24.061 ;
     RECT  47.34 23.971 47.358 24.097 ;
     RECT  47.34 24.097 48.006 24.169 ;
     RECT  0.036 21.811 5.346 24.241 ;
     RECT  47.16 24.169 48.006 24.241 ;
     RECT  49.32 24.061 49.374 24.241 ;
     RECT  47.16 24.241 49.374 24.359 ;
     RECT  47.16 24.359 49.338 24.395 ;
     RECT  50.724 23.701 50.742 24.571 ;
     RECT  50.688 24.571 50.742 24.629 ;
     RECT  48.636 24.395 49.338 24.701 ;
     RECT  0.036 24.241 5.67 24.781 ;
     RECT  45.615 2.413 45.897 24.979 ;
     RECT  45.504 24.979 45.897 25.015 ;
     RECT  50.724 24.629 50.742 25.037 ;
     RECT  47.16 24.395 47.898 25.051 ;
     RECT  24.015 2.413 24.297 25.177 ;
     RECT  45 25.015 45.897 25.177 ;
     RECT  47.124 25.051 47.898 25.205 ;
     RECT  43.956 25.051 43.974 25.213 ;
     RECT  44.748 25.177 45.897 25.213 ;
     RECT  42.912 25.213 42.93 25.249 ;
     RECT  6.84 25.177 6.858 25.277 ;
     RECT  0.036 24.781 5.706 25.285 ;
     RECT  0.036 25.285 5.814 25.321 ;
     RECT  24.015 25.177 24.678 25.321 ;
     RECT  43.956 25.213 45.897 25.411 ;
     RECT  24.015 25.321 24.858 25.439 ;
     RECT  24.015 25.439 24.678 25.475 ;
     RECT  38.772 25.249 38.79 25.547 ;
     RECT  42.768 25.249 42.93 25.555 ;
     RECT  47.448 25.205 47.898 25.591 ;
     RECT  48.636 24.701 48.906 25.591 ;
     RECT  42.372 25.555 43.218 25.613 ;
     RECT  43.956 25.411 46.314 25.613 ;
     RECT  42.912 25.613 43.218 25.709 ;
     RECT  44.1 25.613 46.314 25.709 ;
     RECT  44.1 25.709 44.118 25.745 ;
     RECT  0.036 25.321 5.958 25.825 ;
     RECT  0.036 25.825 6.03 25.861 ;
     RECT  47.448 25.591 48.906 25.861 ;
     RECT  47.448 25.861 48.942 26.011 ;
     RECT  0.036 25.861 6.174 26.015 ;
     RECT  18.615 2.413 18.897 26.095 ;
     RECT  0.036 26.015 5.958 26.123 ;
     RECT  47.16 26.011 48.942 26.131 ;
     RECT  45 25.709 46.314 26.249 ;
     RECT  45.576 26.249 46.314 26.257 ;
     RECT  45.576 26.257 46.386 26.285 ;
     RECT  2.304 26.123 5.85 26.393 ;
     RECT  47.16 26.131 49.194 26.393 ;
     RECT  45.615 26.285 46.386 26.401 ;
     RECT  47.16 26.393 48.402 26.401 ;
     RECT  6.84 26.293 6.858 26.429 ;
     RECT  49.176 26.393 49.194 26.491 ;
     RECT  45.615 26.401 48.402 26.519 ;
     RECT  50.688 25.435 50.706 26.519 ;
     RECT  45.615 26.519 46.854 26.555 ;
     RECT  2.304 26.393 5.67 26.591 ;
     RECT  47.88 26.519 48.402 26.591 ;
     RECT  49.176 26.491 49.338 26.591 ;
     RECT  47.88 26.591 47.934 26.699 ;
     RECT  50.184 26.731 50.67 26.789 ;
     RECT  42.912 25.709 42.93 26.797 ;
     RECT  49.176 26.591 49.194 26.825 ;
     RECT  18.576 26.095 18.897 26.833 ;
     RECT  42.912 26.797 43.326 26.941 ;
     RECT  0.036 26.123 1.494 26.969 ;
     RECT  0.072 26.969 1.494 27.005 ;
     RECT  42.516 26.941 43.326 27.031 ;
     RECT  44.1 26.905 44.118 27.031 ;
     RECT  45.615 26.555 46.386 27.059 ;
     RECT  42.516 27.031 44.118 27.167 ;
     RECT  42.516 27.167 43.362 27.203 ;
     RECT  44.1 27.167 44.118 27.203 ;
     RECT  42.516 27.203 43.326 27.307 ;
     RECT  42.372 27.307 43.326 27.329 ;
     RECT  42.372 27.329 42.39 27.365 ;
     RECT  45.615 27.059 45.897 27.481 ;
     RECT  50.652 26.789 50.67 27.595 ;
     RECT  45.108 27.481 45.897 27.599 ;
     RECT  43.164 27.329 43.326 27.635 ;
     RECT  44.352 27.301 44.37 27.635 ;
     RECT  24.015 25.475 24.297 27.679 ;
     RECT  23.904 27.679 24.297 27.715 ;
     RECT  47.016 27.355 47.034 27.715 ;
     RECT  2.304 26.591 5.49 27.751 ;
     RECT  23.688 27.715 24.297 27.751 ;
     RECT  47.016 27.715 47.178 27.751 ;
     RECT  47.916 26.699 47.934 27.751 ;
     RECT  49.32 27.481 49.338 27.751 ;
     RECT  47.016 27.751 49.338 27.869 ;
     RECT  50.652 27.595 50.706 27.869 ;
     RECT  23.688 27.751 24.822 27.877 ;
     RECT  25.884 27.751 25.902 27.905 ;
     RECT  47.016 27.869 47.934 27.905 ;
     RECT  48.888 27.869 49.338 27.905 ;
     RECT  0.072 27.005 1.458 27.913 ;
     RECT  2.304 27.751 5.922 27.913 ;
     RECT  23.508 27.877 24.894 27.917 ;
     RECT  26.748 27.679 26.766 27.941 ;
     RECT  43.308 27.635 43.326 27.941 ;
     RECT  47.916 27.905 47.934 27.941 ;
     RECT  50.688 27.869 50.706 28.139 ;
     RECT  49.104 27.905 49.338 28.211 ;
     RECT  0.072 27.913 5.922 28.409 ;
     RECT  0.072 28.409 5.274 28.715 ;
     RECT  0.072 28.715 0.558 28.733 ;
     RECT  18.576 26.833 19.098 30.541 ;
     RECT  0.072 28.733 0.306 30.749 ;
     RECT  18.576 30.541 19.674 31.081 ;
     RECT  1.404 28.715 5.274 31.109 ;
     RECT  0.072 30.749 0.198 31.729 ;
     RECT  1.404 31.109 3.978 31.829 ;
     RECT  0.072 31.729 0.558 32.189 ;
     RECT  34.815 2.413 35.097 33.241 ;
     RECT  34.815 33.241 35.694 33.259 ;
     RECT  36.792 33.259 36.81 33.305 ;
     RECT  34.815 33.259 35.802 33.539 ;
     RECT  18.576 31.081 20.106 33.619 ;
     RECT  1.404 31.829 3.69 33.953 ;
     RECT  0.072 32.189 0.198 34.781 ;
     RECT  0.072 34.781 0.162 35.117 ;
     RECT  0.144 35.117 0.162 35.213 ;
     RECT  31.392 36.751 31.41 36.797 ;
     RECT  31.068 36.811 31.086 36.851 ;
     RECT  1.404 33.953 2.697 36.941 ;
     RECT  2.052 36.941 2.697 37.805 ;
     RECT  2.304 37.805 2.697 38.551 ;
     RECT  3.42 33.953 3.69 38.551 ;
     RECT  2.304 38.551 3.69 38.705 ;
     RECT  2.415 38.705 3.69 38.849 ;
     RECT  2.415 38.849 3.438 38.939 ;
     RECT  5.004 31.109 5.166 39.011 ;
     RECT  6.012 28.453 6.03 39.317 ;
     RECT  0.108 39.055 0.126 39.865 ;
     RECT  0.108 39.865 0.162 40.829 ;
     RECT  26.604 40.651 26.622 40.829 ;
     RECT  0.144 40.829 0.162 41.261 ;
     RECT  23.616 27.917 24.297 46.769 ;
     RECT  16.848 24.133 16.866 46.777 ;
     RECT  16.02 46.777 16.038 46.813 ;
     RECT  16.848 46.777 16.938 46.813 ;
     RECT  16.02 46.813 17.154 46.849 ;
     RECT  16.02 46.849 17.334 47.011 ;
     RECT  18.252 33.619 20.106 47.011 ;
     RECT  16.02 47.011 20.106 47.117 ;
     RECT  5.04 39.011 5.166 47.219 ;
     RECT  16.02 47.117 17.478 47.281 ;
     RECT  2.415 38.939 3.33 47.309 ;
     RECT  14.832 47.119 14.85 47.309 ;
     RECT  15.912 47.281 17.478 47.695 ;
     RECT  15.588 47.695 17.478 47.857 ;
     RECT  18.252 47.117 20.106 47.857 ;
     RECT  15.588 47.857 20.106 48.271 ;
     RECT  34.815 33.539 35.097 48.469 ;
     RECT  15.156 48.271 20.106 48.475 ;
     RECT  15.012 48.475 20.106 48.505 ;
     RECT  22.068 48.469 22.158 48.541 ;
     RECT  31.14 48.541 31.158 48.667 ;
     RECT  21.996 48.541 22.158 48.739 ;
     RECT  24.015 46.769 24.297 48.739 ;
     RECT  31.14 48.667 31.662 48.739 ;
     RECT  23.616 48.739 24.297 48.775 ;
     RECT  34.344 48.469 35.097 48.775 ;
     RECT  21.888 48.739 22.158 48.811 ;
     RECT  26.532 48.775 26.694 48.811 ;
     RECT  5.04 47.219 5.058 48.839 ;
     RECT  21.888 48.811 22.23 48.901 ;
     RECT  31.068 48.739 31.662 48.901 ;
     RECT  15.012 48.505 20.178 48.929 ;
     RECT  34.236 48.775 35.766 48.937 ;
     RECT  21.852 48.901 22.23 48.973 ;
     RECT  23.436 48.775 24.297 48.973 ;
     RECT  25.056 48.775 25.074 48.973 ;
     RECT  26.532 48.811 27.378 48.973 ;
     RECT  34.236 48.937 36.018 48.973 ;
     RECT  21.096 46.885 21.114 49.009 ;
     RECT  21.852 48.973 24.297 49.009 ;
     RECT  21.096 49.009 24.297 49.045 ;
     RECT  25.056 48.973 25.182 49.045 ;
     RECT  21.096 49.045 25.182 49.081 ;
     RECT  31.068 48.901 31.914 49.081 ;
     RECT  34.164 48.973 36.018 49.109 ;
     RECT  21.096 49.081 25.254 49.171 ;
     RECT  29.415 2.413 29.697 49.171 ;
     RECT  30.78 49.081 32.382 49.171 ;
     RECT  29.415 49.171 32.382 49.199 ;
     RECT  21.096 49.171 25.434 49.207 ;
     RECT  15.48 48.929 20.178 49.243 ;
     RECT  26.172 48.973 27.378 49.243 ;
     RECT  33.12 49.171 33.138 49.271 ;
     RECT  29.415 49.199 32.202 49.307 ;
     RECT  15.48 49.243 20.286 49.351 ;
     RECT  21.06 49.207 25.434 49.351 ;
     RECT  26.172 49.243 27.918 49.351 ;
     RECT  34.815 49.109 36.018 49.351 ;
     RECT  15.48 49.351 27.918 49.379 ;
     RECT  29.415 49.307 30.114 49.379 ;
     RECT  2.415 47.309 2.697 49.427 ;
     RECT  7.815 2.413 8.097 49.427 ;
     RECT  13.215 2.413 13.497 49.427 ;
     RECT  40.215 2.413 40.497 49.427 ;
     RECT  45.615 27.599 45.897 49.427 ;
     RECT  22.644 49.379 27.918 49.469 ;
     RECT  29.415 49.379 30.006 49.469 ;
     RECT  34.815 49.351 36.45 49.469 ;
     RECT  29.415 49.469 29.862 49.477 ;
     RECT  15.48 49.379 21.69 49.505 ;
     RECT  31.32 49.307 32.202 49.505 ;
     RECT  16.164 49.505 21.69 49.517 ;
     RECT  22.644 49.469 27.81 49.517 ;
     RECT  29.304 49.477 29.862 49.517 ;
     RECT  31.32 49.505 32.022 49.517 ;
     RECT  20.052 49.517 21.69 49.565 ;
     RECT  22.644 49.517 24.105 49.565 ;
     RECT  25.02 49.517 27.81 49.565 ;
     RECT  29.415 49.517 29.862 49.565 ;
     RECT  32.004 49.517 32.022 49.565 ;
     RECT  16.164 49.517 16.614 49.577 ;
     RECT  17.46 49.517 19.026 49.577 ;
     RECT  20.052 49.565 20.07 49.577 ;
     RECT  21.132 49.565 21.69 49.577 ;
     RECT  25.02 49.565 27.09 49.577 ;
     RECT  33.228 49.315 33.894 49.577 ;
     RECT  34.815 49.469 36.342 49.577 ;
     RECT  22.896 49.565 24.105 49.613 ;
     RECT  2.415 49.427 2.505 49.697 ;
     RECT  7.815 49.427 7.905 49.697 ;
     RECT  13.215 49.427 13.305 49.697 ;
     RECT  18.615 49.577 18.81 49.697 ;
     RECT  23.256 49.613 24.105 49.697 ;
     RECT  29.415 49.565 29.574 49.697 ;
     RECT  34.815 49.577 34.905 49.697 ;
     RECT  40.215 49.427 40.305 49.697 ;
     RECT  45.615 49.427 45.705 49.697 ;
     RECT  18.792 49.697 18.81 49.805 ;
     RECT  29.556 49.697 29.574 49.805 ;
     RECT  26.172 49.577 27.09 50.189 ;
     RECT  21.672 49.577 21.69 50.765 ;
     RECT  23.256 49.697 23.886 50.765 ;
     RECT  25.02 49.577 25.362 50.765 ;
     RECT  33.876 49.577 33.894 50.765 ;
     RECT  36.324 49.577 36.342 50.765 ;
     RECT  26.604 50.189 26.622 51.725 ;
    LAYER M4 ;
     RECT  0.025 13.488 0.06 13.512 ;
     RECT  0.06 10.56 0.137 41.256 ;
     RECT  0.137 13.584 0.173 39.096 ;
     RECT  0.137 40.368 0.173 41.256 ;
     RECT  0.173 13.584 0.209 32.184 ;
     RECT  0.173 33.888 0.209 39.096 ;
     RECT  0.209 17.904 0.569 32.184 ;
     RECT  0.209 13.584 0.893 16.92 ;
     RECT  0.893 15.744 1.433 16.92 ;
     RECT  0.137 10.56 2.408 12.312 ;
     RECT  0.893 13.584 2.408 14.472 ;
     RECT  1.433 16.176 2.408 16.92 ;
     RECT  0.569 17.904 2.408 23.112 ;
     RECT  0.569 24.384 2.408 31.32 ;
     RECT  0.209 33.888 2.408 33.912 ;
     RECT  0.209 35.616 2.408 39.096 ;
     RECT  2.408 2.148 2.512 49.692 ;
     RECT  2.512 2.418 2.704 49.422 ;
     RECT  2.704 10.656 2.765 10.68 ;
     RECT  2.704 33.888 2.765 33.912 ;
     RECT  2.704 22.272 2.873 22.296 ;
     RECT  2.704 26.544 2.873 27.432 ;
     RECT  2.704 30.864 2.873 30.888 ;
     RECT  2.704 28.944 2.909 28.968 ;
     RECT  2.704 16.896 3.053 16.92 ;
     RECT  2.704 20.4 3.089 20.952 ;
     RECT  2.873 26.544 3.097 27.048 ;
     RECT  3.097 26.544 3.197 27 ;
     RECT  2.704 18.432 3.233 18.456 ;
     RECT  3.089 20.4 3.341 20.424 ;
     RECT  2.704 13.584 3.413 14.136 ;
     RECT  3.413 13.584 3.737 13.608 ;
     RECT  3.197 26.976 3.881 27 ;
     RECT  2.704 12.288 5.357 12.312 ;
     RECT  5.857 26.064 5.969 26.088 ;
     RECT  7.808 2.148 7.912 49.692 ;
     RECT  7.912 2.418 8.104 49.422 ;
     RECT  13.208 2.148 13.312 49.692 ;
     RECT  13.312 2.418 13.504 49.422 ;
     RECT  15.001 48.48 15.505 48.504 ;
     RECT  15.505 48.48 15.577 49.368 ;
     RECT  15.577 47.904 15.779 49.368 ;
     RECT  15.779 47.904 16.477 48.456 ;
     RECT  16.477 47.088 16.589 48.456 ;
     RECT  16.589 48.432 16.837 48.456 ;
     RECT  16.124 49.536 16.837 49.56 ;
     RECT  16.837 48.432 17.453 49.56 ;
     RECT  16.589 47.088 17.561 47.112 ;
     RECT  15.301 36.816 18.608 36.84 ;
     RECT  17.845 47.904 18.608 47.928 ;
     RECT  17.453 49.296 18.608 49.56 ;
     RECT  18.608 2.148 18.712 49.692 ;
     RECT  18.712 2.418 18.737 49.692 ;
     RECT  18.737 2.418 18.821 49.8 ;
     RECT  18.821 2.418 18.904 49.512 ;
     RECT  18.904 48.768 19.043 49.512 ;
     RECT  19.043 49.104 20.012 49.512 ;
     RECT  20.012 49.104 21.395 49.56 ;
     RECT  21.661 50.736 22.259 50.76 ;
     RECT  21.395 49.104 22.604 49.272 ;
     RECT  23.557 40.464 23.597 40.488 ;
     RECT  23.245 50.736 23.987 50.76 ;
     RECT  23.497 27.888 24.008 27.912 ;
     RECT  18.904 36.816 24.008 36.84 ;
     RECT  23.597 40.464 24.008 41.016 ;
     RECT  18.904 47.568 24.008 47.592 ;
     RECT  22.604 49.104 24.008 49.56 ;
     RECT  24.008 2.148 24.112 49.692 ;
     RECT  24.112 2.418 24.304 49.512 ;
     RECT  24.304 49.104 24.509 49.512 ;
     RECT  24.509 49.104 24.851 49.368 ;
     RECT  24.304 27.888 24.905 27.912 ;
     RECT  25.009 50.736 25.715 50.76 ;
     RECT  24.851 49.104 26.101 49.128 ;
     RECT  26.101 49.104 26.161 49.56 ;
     RECT  26.161 49.104 26.237 50.184 ;
     RECT  26.237 49.104 26.485 49.128 ;
     RECT  26.485 49.008 26.813 49.128 ;
     RECT  26.813 49.104 26.885 49.128 ;
     RECT  26.593 51.696 27.011 51.72 ;
     RECT  26.237 50.16 27.443 50.184 ;
     RECT  27.781 49.536 27.875 49.56 ;
     RECT  24.304 36.816 29.408 36.84 ;
     RECT  26.593 40.656 29.408 40.68 ;
     RECT  29.125 49.488 29.408 49.512 ;
     RECT  29.408 2.148 29.512 49.692 ;
     RECT  29.512 2.418 29.516 49.692 ;
     RECT  29.516 2.418 29.603 49.8 ;
     RECT  29.603 2.418 29.704 49.56 ;
     RECT  29.704 49.536 30.035 49.56 ;
     RECT  29.704 36.816 31.097 36.84 ;
     RECT  31.34 36.768 31.427 36.792 ;
     RECT  29.704 40.656 31.427 40.68 ;
     RECT  31.285 49.488 31.717 49.512 ;
     RECT  31.717 49.008 31.817 49.512 ;
     RECT  31.993 49.536 32.195 49.56 ;
     RECT  33.865 50.736 34.355 50.76 ;
     RECT  31.381 33.312 34.808 33.336 ;
     RECT  33.217 49.536 34.808 49.56 ;
     RECT  34.808 2.148 34.912 49.692 ;
     RECT  34.912 2.418 35.104 49.56 ;
     RECT  35.104 33.264 35.705 33.336 ;
     RECT  35.104 49.536 36.083 49.56 ;
     RECT  36.313 50.736 36.515 50.76 ;
     RECT  35.705 33.264 40.208 33.288 ;
     RECT  40.208 2.148 40.312 49.692 ;
     RECT  40.312 2.418 40.504 49.422 ;
     RECT  42.332 27.312 42.373 27.336 ;
     RECT  42.373 27.168 42.419 27.336 ;
     RECT  40.504 33.264 42.419 33.288 ;
     RECT  42.419 27.168 43.373 27.192 ;
     RECT  42.361 25.584 43.945 25.608 ;
     RECT  43.945 25.056 43.985 25.608 ;
     RECT  43.985 25.056 45.608 25.08 ;
     RECT  45.565 26.256 45.608 26.28 ;
     RECT  45.608 2.148 45.712 49.692 ;
     RECT  45.712 2.418 45.904 49.422 ;
     RECT  45.904 26.256 47.125 26.28 ;
     RECT  47.125 26.016 47.171 26.28 ;
     RECT  47.005 27.36 47.171 27.384 ;
     RECT  47.105 24.48 47.189 24.504 ;
     RECT  47.171 26.016 47.212 26.04 ;
     RECT  50.173 26.736 50.641 26.76 ;
     RECT  50.641 26.736 50.677 27.192 ;
     RECT  50.677 24.576 50.713 27.624 ;
     RECT  50.713 24.144 51.804 27.624 ;
    LAYER M5 ;
     RECT  2.4 2.137 2.52 2.151 ;
     RECT  7.8 2.137 7.92 2.151 ;
     RECT  13.2 2.137 13.32 2.151 ;
     RECT  18.6 2.137 18.72 2.151 ;
     RECT  24 2.137 24.12 2.151 ;
     RECT  29.4 2.137 29.52 2.151 ;
     RECT  34.8 2.137 34.92 2.151 ;
     RECT  40.2 2.137 40.32 2.151 ;
     RECT  45.6 2.137 45.72 2.151 ;
     RECT  2.4 2.151 2.712 26.581 ;
     RECT  2.4 26.581 3.048 27.059 ;
     RECT  42.72 25.573 42.744 27.157 ;
     RECT  42.384 27.157 42.744 27.203 ;
     RECT  47.136 24.469 47.16 27.395 ;
     RECT  24 2.151 24.312 27.877 ;
     RECT  42.384 27.203 42.408 33.299 ;
     RECT  23.568 27.877 24.312 40.499 ;
     RECT  31.392 33.301 31.416 40.691 ;
     RECT  18.6 2.151 18.912 47.557 ;
     RECT  23.616 40.499 24.312 47.603 ;
     RECT  15.312 36.805 15.336 49.333 ;
     RECT  24 47.603 24.312 49.333 ;
     RECT  18.6 47.557 19.032 49.477 ;
     RECT  29.4 2.151 29.712 49.477 ;
     RECT  31.728 48.997 31.752 49.477 ;
     RECT  15.312 49.333 15.768 49.525 ;
     RECT  17.04 49.477 17.064 49.525 ;
     RECT  18.336 49.477 19.656 49.525 ;
     RECT  21.792 49.237 21.816 49.525 ;
     RECT  24 49.333 24.84 49.525 ;
     RECT  29.136 49.477 29.712 49.525 ;
     RECT  31.296 49.477 31.752 49.525 ;
     RECT  34.8 2.151 35.112 49.525 ;
     RECT  2.4 27.059 2.712 49.689 ;
     RECT  7.8 2.151 8.112 49.689 ;
     RECT  13.2 2.151 13.512 49.689 ;
     RECT  40.2 2.151 40.512 49.689 ;
     RECT  45.6 2.151 45.912 49.689 ;
     RECT  2.4 49.689 2.52 49.703 ;
     RECT  7.8 49.689 7.92 49.703 ;
     RECT  13.2 49.689 13.32 49.703 ;
     RECT  15.312 49.525 24.84 49.703 ;
     RECT  33.456 49.525 36.072 49.703 ;
     RECT  40.2 49.689 40.32 49.703 ;
     RECT  45.6 49.689 45.72 49.703 ;
     RECT  26.112 49.525 26.136 50.149 ;
     RECT  27.84 49.525 27.864 50.149 ;
     RECT  15.312 49.703 23.112 50.725 ;
     RECT  24.384 49.703 24.84 50.725 ;
     RECT  26.112 50.149 27.864 50.725 ;
     RECT  33.456 49.703 33.912 50.725 ;
     RECT  35.616 49.703 36.072 50.725 ;
     RECT  15.312 50.725 27.864 51.792 ;
     RECT  29.136 49.525 30.024 51.792 ;
     RECT  31.296 49.525 32.184 51.792 ;
     RECT  33.456 50.725 34.344 51.792 ;
     RECT  35.616 50.725 36.504 51.792 ;
     RECT  45.912 24.469 47.136 27.395 ;
     RECT  15.768 49.477 17.04 49.525 ;
     RECT  17.064 49.477 18.336 49.525 ;
     RECT  24.84 49.525 26.112 50.725 ;
     RECT  27.864 49.525 29.136 51.708 ;
     RECT  30.024 49.525 31.296 51.708 ;
     RECT  32.184 49.525 33.456 51.708 ;
     RECT  23.112 49.703 24.384 50.725 ;
     RECT  33.912 49.703 35.616 50.725 ;
     RECT  34.344 50.725 35.616 51.708 ;
     RECT  27.912 51.708 28.224 51.792 ;
     RECT  28.344 51.708 28.656 51.792 ;
     RECT  28.776 51.708 29.088 51.792 ;
     RECT  30.072 51.708 30.384 51.792 ;
     RECT  30.504 51.708 30.816 51.792 ;
     RECT  30.936 51.708 31.248 51.792 ;
     RECT  32.232 51.708 32.544 51.792 ;
     RECT  32.664 51.708 32.976 51.792 ;
     RECT  33.096 51.708 33.408 51.792 ;
     RECT  34.392 51.708 34.704 51.792 ;
     RECT  34.824 51.708 35.136 51.792 ;
     RECT  35.256 51.708 35.568 51.792 ;
  END
END dsfd_vm_static_read_v3
END LIBRARY
